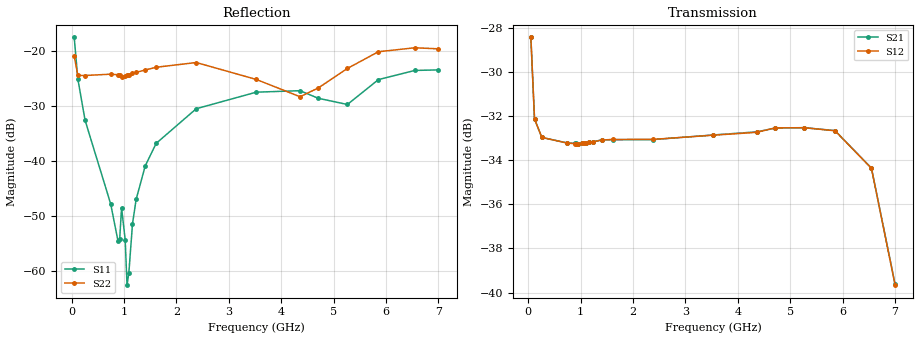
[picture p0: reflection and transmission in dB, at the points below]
! Integrated Device Technology
! Corporate Headquarters
! 6024 Silver Creek Valley Road
! San Jose, CA 95138  USA
! Phone:  1-408-284-8200
! Toll Free:  1-800-223-1366
! Webpage:  http://www.idt.com/
! Timing and RF Division
! 515 Groton Road, Suite 102
! Westford, MA 01886-6024
! Device:  F2258
! Description: Voltage Variable RF Attenuator
! Frequency:  50.0 -  6000.00 MHz
! Package:  3x3 mm Thin QFN Plastic Package: 16 pin
! Ports:  2 RF, 2 DC
!  Pin  1  = NC
!  Pin  2  = NC
!  Pin  3  = RF2  = Port 2
!  Pin  4  = GND
!  Pin  5  = Vdd
!  Pin  6  = NC
!  Pin  7  = VCTRL
!  Pin  8  = NC
!  Pin  9  = GND
!  Pin 10  = RF1  = Port 1
!  Pin 11  = NC
!  Pin 12  = NC
!  Pin 13  = NC
!  Pin 14  = NC
!  Pin 15  = NC
!  Pin 16  = NC
! Vcntrl:  1.790 Volts
! Vdd:  +3.300 Volts
! Current:  1.157 mA
! Data:  The device was measured on a the F2258 evaluation board which has
!  individual transmission lines to the RF pins.  Data was collected
!  using a calibrated network analyzer.  The evaluation board was
!  de-embedded using a TRL calibration technique.
!  The reference plane is the edge of the package pin.
! Misc:  SN 10
!  Action Tracker AT0285
! Date Measured:  2014-12-10
! Date:  2016-01-13  MJV
! Note:
!  Integrated Device Technology supplies this data as a sample of measured
!  data at the package pin for this product.  Your particular data for this
!  product may vary.
!  Data was taken at 25 degrees C.
!  Integrated Device Technology reserves the right to change this data at anytime.
!Freq_(GHz)  S11M_(dB)  S11P_(deg)  S21M_(dB)  S21P_(deg)  S12M_(dB)  S12P_(deg)  S22M_(dB)  S22P_(deg)
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# GHz S dB R 50
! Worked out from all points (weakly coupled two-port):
!   201 points, 50 MHz to 7 GHz, reference 50 ohm
!   highest |S21| = -28.44 dB at 50 MHz (marker M1); lowest = -39.6 dB at 7 GHz (marker M2)
!   lowest |S11| = -62.6 dB at 1.058 GHz (marker M3), VSWR 1.00, Z = 49.9 + j0.0384 ohm
!   |S11| at or under -10 dB: start of sweep to end of sweep
!   |S22| runs from -28.3 to -19.2 dB; largest |S21 - S12| = 0.00011
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0.05  -17.53 -110.6  -28.44 -59.7  -28.44 -59.7  -20.93 -87.0
0.1195  -25.11 -106.2  -32.13 -31.5  -32.14 -31.5  -24.43 -37.6
0.2585  -32.64 -110.4  -32.97 -16.6  -32.97 -16.6  -24.46 -15.9
0.745  -47.77 -137.5  -33.22 -9.7  -33.23 -9.7  -24.22 -6.7
0.884  -54.47 167.0  -33.24 -9.6  -33.25 -9.6  -24.33 -7.3
0.91875  -54.11 145.6  -33.24 -9.6  -33.25 -9.6  -24.36 -7.5
0.9535  -48.48 -157.3  -33.26 -9.6  -33.26 -9.6  -24.75 -5.7
1.023  -54.34 176.4  -33.23 -9.7  -33.24 -9.6  -24.51 -6.8
1.05775  -62.57 148.9  -33.22 -9.7  -33.23 -9.7  -24.38 -6.6
1.0925  -60.35 97.7  -33.22 -9.7  -33.21 -9.7  -24.32 -6.8
1.162  -51.45 57.7  -33.20 -9.9  -33.19 -9.9  -24.06 -7.0
1.2315  -47.00 39.8  -33.17 -10.1  -33.17 -10.1  -23.89 -7.2
1.40525  -40.89 30.7  -33.08 -11.1  -33.09 -11.1  -23.46 -7.3
1.61375  -36.80 30.8  -33.08 -12.5  -33.06 -12.5  -22.96 -8.9
2.37825  -30.50 47.1  -33.07 -17.2  -33.06 -17.2  -22.10 -10.2
3.525  -27.49 91.1  -32.86 -25.2  -32.87 -25.2  -25.18 -10.9
4.359  -27.22 104.5  -32.72 -32.1  -32.74 -32.0  -28.32 -22.2
4.7065  -28.60 95.3  -32.55 -35.3  -32.54 -35.3  -26.73 -32.4
5.2625  -29.73 53.5  -32.53 -41.4  -32.53 -41.5  -23.18 -38.7
5.85325  -25.21 29.4  -32.66 -51.1  -32.67 -51.1  -20.14 -39.9
6.54825  -23.54 44.7  -34.36 -68.6  -34.37 -68.6  -19.42 -65.8
7  -23.44 84.2  -39.62 -66.3  -39.66 -66.2  -19.61 -123.3
